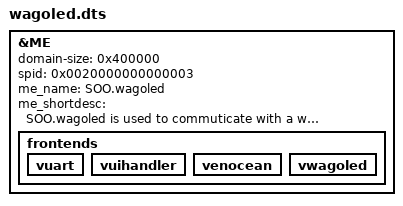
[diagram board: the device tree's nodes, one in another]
/*
 * Copyright (C) 2022 Mattia Gallacchi <mattia.gallaccchi@heig-vd.ch>
 *
 * This program is free software; you can redistribute it and/or modify
 * it under the terms of the GNU General Public License version 2 as
 * published by the Free Software Foundation.
 *
 * This program is distributed in the hope that it will be useful,
 * but WITHOUT ANY WARRANTY; without even the implied warranty of
 * MERCHANTABILITY or FITNESS FOR A PARTICULAR PURPOSE.  See the
 * GNU General Public License for more details.
 *
 * You should have received a copy of the GNU General Public License
 * along with this program; if not, write to the Free Software
 * Foundation, Inc., 51 Franklin St, Fifth Floor, Boston, MA  02110-1301  USA
 *
 */

/dts-v1/;

#include "so3virt.dtsi"

&ME {
	/* 4 MB is enough */
	domain-size = <0x400000>;
	
	/* SPID on 128-bit encoding */
	spid = /bits/ 64 <0x0020000000000003>;
		
	/* Name of this ME */
	me_name = "SOO.wagoled";
		
	/* Short description */
	me_shortdesc =
			
"SOO.wagoled is used to commuticate with a wago cluster to control LEDs \
on DALI bus";

	frontends {
		
		/* Enabling the console */
		vuart {
			status = "ok";
		};
	  
		vuihandler {
			status = "ok";
		};

		venocean {
			status = "ok";
		};

		vwagoled {
			status = "ok";
		};
	};
	
};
